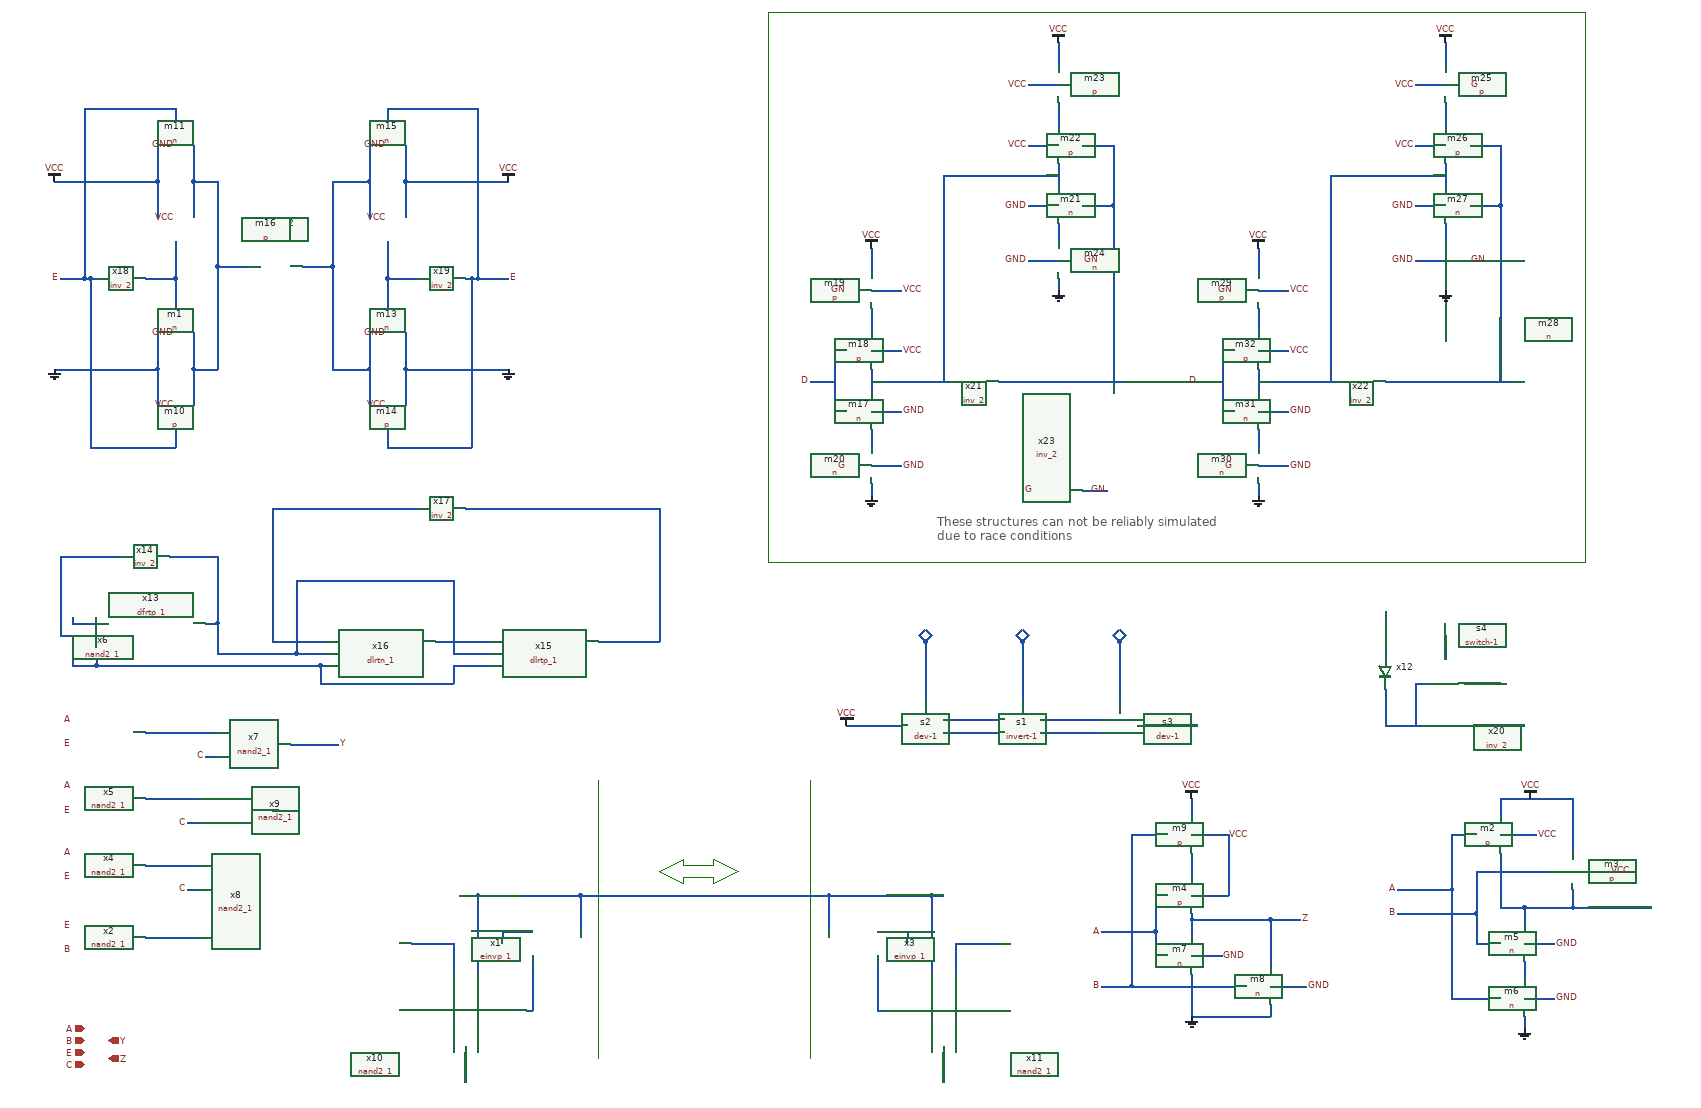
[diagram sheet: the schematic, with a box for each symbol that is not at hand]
v {xschem version=2.9.9 file_version=1.2 }
G {}
K {}
V {}
S {}
E {}
L 4 920 -590 920 -130 {dash=3}
L 4 1270 -590 1270 -130 {dash=3}
P 4 11 1110 -450 1060 -450 1060 -460 1020 -440 1060 -420 1060 -430 1110 -430 1110 -420 1150 -440 1110 -460 1110 -450 {}
P 4 5 1200 -1860 1200 -950 2550 -950 2550 -1860 1200 -1860 {dash=3}
T {These structures can not be reliably simulated
due to race conditions} 1480 -1030 0 0 0.6 0.6 {}
N 170 -330 260 -330 { lab=#net1}
N 170 -450 260 -450 { lab=#net2}
N 240 -410 260 -410 { lab=C}
N 170 -560 260 -560 { lab=#net3}
N 240 -520 260 -520 { lab=C}
N 270 -630 290 -630 { lab=C}
N 410 -650 490 -650 { lab=Y}
N 170 -670 290 -670 { lab=#net4}
N 380 -540 390 -540 { lab=#net5}
N 890 -400 890 -340 { lab=#net6}
N 890 -400 1300 -400 { lab=#net6}
N 720 -400 720 -270 { lab=#net6}
N 700 -150 700 -90 { lab=#net7}
N 680 -320 680 -270 { lab=#net8}
N 610 -320 680 -320 { lab=#net8}
N 810 -300 810 -210 { lab=#net9}
N 800 -210 810 -210 { lab=#net9}
N 690 -400 720 -400 { lab=#net6}
N 1470 -400 1490 -400 { lab=#net6}
N 760 -340 810 -340 { lab=#net10}
N 1300 -400 1300 -340 { lab=#net6}
N 1470 -400 1470 -270 { lab=#net6}
N 1490 -150 1490 -90 { lab=#net11}
N 1510 -320 1510 -270 { lab=#net12}
N 1510 -320 1580 -320 { lab=#net12}
N 1380 -300 1380 -210 { lab=#net13}
N 1380 -210 1390 -210 { lab=#net13}
N 1380 -340 1430 -340 { lab=#net14}
N 760 -340 760 -320 { lab=#net10}
N 1430 -340 1430 -320 { lab=#net14}
N 720 -400 890 -400 { lab=#net6}
N 1300 -400 1470 -400 { lab=#net6}
N 380 -820 470 -820 { lab=#net15}
N 420 -800 470 -800 { lab=#net16}
N 460 -780 470 -780 { lab=#net17}
N 650 -820 740 -820 { lab=#net18}
N 460 -780 460 -750 { lab=#net17}
N 460 -750 680 -750 { lab=#net17}
N 680 -780 680 -750 { lab=#net17}
N 680 -780 740 -780 { lab=#net17}
N 920 -820 1020 -820 { lab=#net19}
N 420 -920 420 -800 { lab=#net16}
N 680 -800 740 -800 { lab=#net16}
N 420 -920 680 -920 { lab=#net16}
N 680 -920 680 -800 { lab=#net16}
N 270 -850 290 -850 { lab=#net16}
N 290 -960 290 -850 { lab=#net16}
N 210 -960 290 -960 { lab=#net16}
N 30 -960 130 -960 { lab=#net20}
N 30 -960 30 -830 { lab=#net20}
N 30 -830 90 -830 { lab=#net20}
N 50 -850 90 -850 { lab=#net21}
N 50 -860 50 -850 { lab=#net21}
N 90 -780 460 -780 { lab=#net17}
N 90 -810 90 -780 { lab=#net17}
N 50 -780 90 -780 { lab=#net17}
N 50 -790 50 -780 { lab=#net17}
N 1900 -360 1900 -330 { lab=Z}
N 1900 -270 1900 -200 { lab=GND}
N 2030 -220 2030 -200 { lab=GND}
N 2030 -360 2030 -280 { lab=Z}
N 1800 -250 1990 -250 { lab=B}
N 1800 -500 1800 -250 { lab=B}
N 1840 -340 1840 -300 { lab=A}
N 1840 -300 1860 -300 { lab=A}
N 1750 -340 1840 -340 { lab=A}
N 1750 -250 1800 -250 { lab=B}
N 1900 -300 1950 -300 { lab=GND}
N 2030 -250 2090 -250 { lab=GND}
N 1900 -470 1900 -430 { lab=#net22}
N 1900 -560 1900 -530 { lab=VCC}
N 2030 -360 2080 -360 { lab=Z}
N 1800 -500 1860 -500 { lab=B}
N 1840 -400 1860 -400 { lab=A}
N 1900 -500 1960 -500 { lab=VCC}
N 1900 -400 1960 -400 { lab=VCC}
N 1960 -500 1960 -400 { lab=VCC}
N 1900 -200 2030 -200 { lab=GND}
N 2450 -290 2450 -260 { lab=#net23}
N 2450 -320 2500 -320 { lab=GND}
N 2450 -230 2500 -230 { lab=GND}
N 2410 -500 2470 -500 { lab=VCC}
N 2530 -440 2590 -440 { lab=VCC}
N 2530 -410 2530 -380 { lab=#net24}
N 2450 -380 2530 -380 { lab=#net24}
N 2410 -470 2410 -380 { lab=#net24}
N 2450 -380 2450 -350 { lab=#net24}
N 2410 -560 2410 -530 { lab=VCC}
N 2410 -560 2530 -560 { lab=VCC}
N 2530 -560 2530 -470 { lab=VCC}
N 2450 -200 2450 -180 { lab=GND}
N 2370 -440 2490 -440 { lab=B}
N 2370 -370 2370 -320 { lab=B}
N 2370 -320 2410 -320 { lab=B}
N 2330 -230 2410 -230 { lab=A}
N 2330 -410 2330 -230 { lab=A}
N 2330 -500 2370 -500 { lab=A}
N 2240 -370 2370 -370 { lab=B}
N 2240 -410 2330 -410 { lab=A}
N 2530 -380 2660 -380 { lab=#net24}
N 700 -1040 1020 -1040 { lab=#net19}
N 1020 -1040 1020 -820 { lab=#net19}
N 380 -1040 620 -1040 { lab=#net15}
N 380 -1040 380 -820 { lab=#net15}
N 380 -800 420 -800 { lab=#net16}
N 1900 -360 2030 -360 { lab=Z}
N 1840 -400 1840 -340 { lab=A}
N 2410 -380 2450 -380 { lab=#net24}
N 2370 -440 2370 -370 { lab=B}
N 2330 -500 2330 -410 { lab=A}
N 1900 -370 1900 -360 { lab=Z}
N 190 -1270 190 -1210 { lab=GND}
N 250 -1270 250 -1210 { lab=#net25}
N 20 -1270 190 -1270 { lab=GND}
N 250 -1270 290 -1270 { lab=#net25}
N 220 -1170 220 -1140 { lab=E}
N 80 -1420 90 -1420 { lab=E}
N 190 -1580 190 -1520 { lab=VCC}
N 250 -1580 250 -1520 { lab=#net25}
N 20 -1580 190 -1580 { lab=VCC}
N 250 -1580 290 -1580 { lab=#net25}
N 220 -1420 220 -1370 { lab=#net26}
N 170 -1420 220 -1420 { lab=#net26}
N 290 -1440 290 -1270 { lab=#net25}
N 290 -1440 340 -1440 { lab=#net25}
N 220 -1700 220 -1680 { lab=E}
N 70 -1700 70 -1420 { lab=E}
N 70 -1700 220 -1700 { lab=E}
N 80 -1420 80 -1140 { lab=E}
N 80 -1140 220 -1140 { lab=E}
N 540 -1270 540 -1210 { lab=#net27}
N 600 -1270 600 -1210 { lab=GND}
N 600 -1270 770 -1270 { lab=GND}
N 480 -1270 540 -1270 { lab=#net27}
N 570 -1170 570 -1140 { lab=E}
N 720 -1420 770 -1420 { lab=E}
N 540 -1580 540 -1520 { lab=#net27}
N 600 -1580 600 -1520 { lab=VCC}
N 600 -1580 770 -1580 { lab=VCC}
N 480 -1580 540 -1580 { lab=#net27}
N 570 -1420 570 -1370 { lab=#net28}
N 570 -1420 620 -1420 { lab=#net28}
N 480 -1440 480 -1270 { lab=#net27}
N 430 -1440 480 -1440 { lab=#net27}
N 570 -1700 720 -1700 { lab=E}
N 570 -1700 570 -1680 { lab=E}
N 720 -1700 720 -1420 { lab=E}
N 710 -1420 710 -1140 { lab=E}
N 570 -1140 710 -1140 { lab=E}
N 190 -1330 190 -1270 { lab=GND}
N 250 -1330 250 -1270 { lab=#net25}
N 190 -1640 190 -1580 { lab=VCC}
N 250 -1640 250 -1580 { lab=#net25}
N 220 -1480 220 -1420 { lab=#net26}
N 290 -1580 290 -1440 { lab=#net25}
N 30 -1420 70 -1420 { lab=E}
N 70 -1420 80 -1420 { lab=E}
N 600 -1330 600 -1270 { lab=GND}
N 540 -1330 540 -1270 { lab=#net27}
N 600 -1640 600 -1580 { lab=VCC}
N 540 -1640 540 -1580 { lab=#net27}
N 570 -1480 570 -1420 { lab=#net28}
N 480 -1580 480 -1440 { lab=#net27}
N 710 -1420 720 -1420 { lab=E}
N 700 -1420 710 -1420 { lab=E}
N 290 -800 380 -800 { lab=#net16}
N 290 -850 290 -800 { lab=#net16}
N 2220 -870 2220 -800 { lab=#net29}
N 2220 -740 2220 -680 { lab=#net30}
N 2220 -680 2280 -680 { lab=#net30}
N 2360 -680 2450 -680 { lab=#net31}
N 1370 -1170 1370 -1140 { lab=#net32}
N 1370 -1270 1370 -1230 { lab=#net33}
N 1370 -1370 1370 -1330 { lab=#net34}
N 1370 -1470 1370 -1430 { lab=VCC}
N 1370 -1080 1370 -1060 { lab=GND}
N 1370 -1110 1420 -1110 { lab=GND}
N 1370 -1200 1420 -1200 { lab=GND}
N 1370 -1300 1420 -1300 { lab=VCC}
N 1370 -1400 1420 -1400 { lab=VCC}
N 1310 -1300 1330 -1300 { lab=D}
N 1310 -1200 1330 -1200 { lab=D}
N 1370 -1250 1500 -1250 { lab=#net33}
N 1310 -1300 1310 -1200 { lab=D}
N 1270 -1250 1310 -1250 { lab=D}
N 2350 -750 2410 -750 { lab=#net35}
N 2270 -750 2290 -750 { lab=#net30}
N 2270 -750 2270 -680 { lab=#net30}
N 2320 -830 2320 -790 { lab=#net36}
N 1680 -1510 1680 -1480 { lab=#net37}
N 1680 -1610 1680 -1570 { lab=#net33}
N 1680 -1710 1680 -1670 { lab=#net38}
N 1680 -1810 1680 -1770 { lab=VCC}
N 1680 -1420 1680 -1400 { lab=GND}
N 1630 -1450 1680 -1450 { lab=GND}
N 1630 -1540 1680 -1540 { lab=GND}
N 1630 -1640 1680 -1640 { lab=VCC}
N 1630 -1740 1680 -1740 { lab=VCC}
N 1720 -1640 1770 -1640 { lab=#net39}
N 1720 -1540 1770 -1540 { lab=#net39}
N 1770 -1640 1770 -1540 { lab=#net39}
N 1770 -1540 1770 -1250 { lab=#net39}
N 1490 -1590 1680 -1590 { lab=#net33}
N 1700 -1250 1790 -1250 { lab=#net39}
N 1580 -1250 1630 -1250 { lab=#net39}
N 1630 -1250 1700 -1250 { lab=#net39}
N 1490 -1590 1490 -1250 { lab=#net33}
N 1720 -1070 1760 -1070 { lab=GN}
N 1490 -670 1590 -670 { lab=#net40}
N 1490 -690 1590 -690 { lab=#net41}
N 1650 -670 1750 -670 { lab=#net42}
N 1650 -690 1750 -690 { lab=#net43}
N 1810 -680 1910 -680 { lab=#net44}
N 1330 -680 1430 -680 { lab=VCC}
N 1460 -820 1460 -720 { lab=#net45}
N 1620 -820 1620 -720 { lab=#net46}
N 1780 -820 1780 -720 { lab=#net47}
N 1450 -830 1460 -820 { lab=#net45}
N 1450 -830 1460 -840 { lab=#net45}
N 1460 -840 1470 -830 { lab=#net45}
N 1460 -820 1470 -830 { lab=#net45}
N 1610 -830 1620 -820 { lab=#net46}
N 1610 -830 1620 -840 { lab=#net46}
N 1620 -840 1630 -830 { lab=#net46}
N 1620 -820 1630 -830 { lab=#net46}
N 1770 -830 1780 -820 { lab=#net47}
N 1770 -830 1780 -840 { lab=#net47}
N 1780 -840 1790 -830 { lab=#net47}
N 1780 -820 1790 -830 { lab=#net47}
N 2010 -1170 2010 -1140 { lab=#net48}
N 2010 -1270 2010 -1230 { lab=#net49}
N 2010 -1370 2010 -1330 { lab=#net50}
N 2010 -1470 2010 -1430 { lab=VCC}
N 2010 -1080 2010 -1060 { lab=GND}
N 2010 -1110 2060 -1110 { lab=GND}
N 2010 -1200 2060 -1200 { lab=GND}
N 2010 -1300 2060 -1300 { lab=VCC}
N 2010 -1400 2060 -1400 { lab=VCC}
N 1950 -1300 1970 -1300 { lab=D}
N 1950 -1200 1970 -1200 { lab=D}
N 2010 -1250 2140 -1250 { lab=#net49}
N 1950 -1300 1950 -1200 { lab=D}
N 1910 -1250 1950 -1250 { lab=D}
N 2320 -1510 2320 -1480 { lab=#net51}
N 2320 -1610 2320 -1570 { lab=#net49}
N 2320 -1710 2320 -1670 { lab=#net52}
N 2320 -1810 2320 -1770 { lab=VCC}
N 2320 -1420 2320 -1400 { lab=GND}
N 2270 -1450 2320 -1450 { lab=GND}
N 2270 -1540 2320 -1540 { lab=GND}
N 2270 -1640 2320 -1640 { lab=VCC}
N 2270 -1740 2320 -1740 { lab=VCC}
N 2360 -1640 2410 -1640 { lab=#net53}
N 2360 -1540 2410 -1540 { lab=#net53}
N 2410 -1640 2410 -1540 { lab=#net53}
N 2410 -1540 2410 -1250 { lab=#net53}
N 2130 -1590 2320 -1590 { lab=#net49}
N 2340 -1250 2430 -1250 { lab=#net53}
N 2220 -1250 2270 -1250 { lab=#net53}
N 2270 -1250 2340 -1250 { lab=#net53}
N 2130 -1590 2130 -1250 { lab=#net49}
C {opin.sym} 110 -160 0 0 { name=p16 lab=Y }
C {inv_2.sym} 1680 -1070 0 0 {name=x23 VGND=VGND VNB=VNB VPB=VPB VPWR=VPWR prefix=sky130_fd_sc_hd__ }
C {ipin.sym} 70 -180 0 0 { name=p20 lab=A }
C {opin.sym} 110 -130 0 0 { name=p4 lab=Z }
C {ipin.sym} 70 -120 0 0 { name=p5 lab=C }
C {title.sym} 160 -30 0 0 {name=l1 author="Stefan Schippers"}
C {lab_pin.sym} 50 -350 0 0 {name=p1 lab=E}
C {nand2_1.sym} 110 -330 0 0 {name=x2 VGND=VGND VNB=VNB VPB=VPB VPWR=VPWR prefix=sky130_fd_sc_hd__ }
C {lab_pin.sym} 50 -310 0 0 {name=p2 lab=B}
C {lab_pin.sym} 50 -470 0 0 {name=p10 lab=A}
C {nand2_1.sym} 110 -450 0 0 {name=x4 VGND=VGND VNB=VNB VPB=VPB VPWR=VPWR prefix=sky130_fd_sc_hd__ }
C {nand2_1.sym} 320 -430 0 0 {name=x8 VGND=VGND VNB=VNB VPB=VPB VPWR=VPWR prefix=sky130_fd_sc_hd__ }
C {lab_pin.sym} 50 -580 0 0 {name=p12 lab=A}
C {nand2_1.sym} 110 -560 0 0 {name=x5 VGND=VGND VNB=VNB VPB=VPB VPWR=VPWR prefix=sky130_fd_sc_hd__ }
C {lab_pin.sym} 50 -540 0 0 {name=p13 lab=E}
C {nand2_1.sym} 320 -540 0 0 {name=x9 VGND=VGND VNB=VNB VPB=VPB VPWR=VPWR prefix=sky130_fd_sc_hd__ }
C {lab_pin.sym} 50 -690 0 0 {name=p14 lab=A}
C {nand2_1.sym} 110 -670 0 0 {name=x6 VGND=VGND VNB=VNB VPB=VPB VPWR=VPWR prefix=sky130_fd_sc_hd__ }
C {lab_pin.sym} 50 -650 0 0 {name=p15 lab=E}
C {nand2_1.sym} 350 -650 0 0 {name=x7 VGND=VGND VNB=VNB VPB=VPB VPWR=VPWR prefix=sky130_fd_sc_hd__ }
C {lab_pin.sym} 490 -650 0 1 {name=p3 lab=Y}
C {lab_pin.sym} 270 -630 0 0 {name=p7 lab=C}
C {lab_pin.sym} 240 -520 0 0 {name=p8 lab=C}
C {lab_pin.sym} 240 -410 0 0 {name=p9 lab=C}
C {noconn.sym} 380 -430 0 1 {name=l2}
C {einvp_1.sym} 850 -340 0 0 {name=x1 VGND=VGND VNB=VNB VPB=VPB VPWR=VPWR prefix=sky130_fd_sc_hd__ }
C {nand2_1.sym} 700 -210 1 0 {name=x10 VGND=VGND VNB=VNB VPB=VPB VPWR=VPWR prefix=sky130_fd_sc_hd__ }
C {einvp_1.sym} 1340 -340 0 1 {name=x3 VGND=VGND VNB=VNB VPB=VPB VPWR=VPWR prefix=sky130_fd_sc_hd__ }
C {nand2_1.sym} 1490 -210 3 1 {name=x11 VGND=VGND VNB=VNB VPB=VPB VPWR=VPWR prefix=sky130_fd_sc_hd__ }
C {dlrtp_1.sym} 830 -800 0 0 {name=x15 VGND=VGND VNB=VNB VPB=VPB VPWR=VPWR prefix=sky130_fd_sc_hd__ }
C {ipin.sym} 70 -140 0 0 { name=p17 lab=E }
C {dlrtn_1.sym} 560 -800 0 0 {name=x16 VGND=VGND VNB=VNB VPB=VPB VPWR=VPWR prefix=sky130_fd_sc_hd__ }
C {dfrtp_1.sym} 180 -830 0 0 {name=x13 VGND=VGND VNB=VNB VPB=VPB VPWR=VPWR prefix=sky130_fd_sc_hd__ }
C {inv_2.sym} 170 -960 0 1 {name=x14 VGND=VGND VNB=VNB VPB=VPB VPWR=VPWR prefix=sky130_fd_sc_hd__ }
C {n.sym} 1880 -300 0 0 {name=m7 model=cmosn w=wn l=lln m=1}
C {n.sym} 2010 -250 0 0 {name=m8 model=cmosn w=wn l=lln m=1}
C {lab_pin.sym} 1750 -340 0 0 {name=p24 lab=A}
C {lab_pin.sym} 1750 -250 0 0 {name=p25 lab=B}
C {lab_pin.sym} 2090 -250 0 1 {name=p27 lab=GND}
C {lab_pin.sym} 1950 -300 0 1 {name=p30 lab=GND}
C {p.sym} 1880 -400 0 0 {name=m4 model=cmosp w=wp l=lp  m=1 }
C {p.sym} 1880 -500 0 0 {name=m9 model=cmosp w=wp l=lp  m=1 }
C {lab_pin.sym} 2080 -360 0 1 {name=p26 lab=Z}
C {lab_pin.sym} 1960 -500 0 1 {name=p31 lab=VCC}
C {gnd.sym} 1900 -200 0 0 {name=l3 lab=GND}
C {vdd.sym} 1900 -560 0 0 {name=l4 lab=VCC}
C {p.sym} 2390 -500 0 0 {name=m2 model=cmosp w=wp l=lp  m=1 }
C {p.sym} 2510 -440 0 0 {name=m3 model=cmosp w=wp l=lp  m=1 }
C {n.sym} 2430 -320 0 0 {name=m5 model=cmosn w=wn l=lln m=1}
C {n.sym} 2430 -230 0 0 {name=m6 model=cmosn w=wn l=lln m=1}
C {lab_pin.sym} 2500 -320 0 1 {name=p22 lab=GND}
C {lab_pin.sym} 2500 -230 0 1 {name=p28 lab=GND}
C {lab_pin.sym} 2470 -500 0 1 {name=p29 lab=VCC}
C {lab_pin.sym} 2590 -440 0 1 {name=p32 lab=VCC}
C {vdd.sym} 2460 -560 0 0 {name=l11 lab=VCC}
C {gnd.sym} 2450 -180 0 0 {name=l12 lab=GND}
C {lab_pin.sym} 2240 -370 0 0 {name=p21 lab=B}
C {lab_pin.sym} 2240 -410 0 0 {name=p23 lab=A}
C {inv_2.sym} 660 -1040 0 1 {name=x17 VGND=VGND VNB=VNB VPB=VPB VPWR=VPWR prefix=sky130_fd_sc_hd__ }
C {n.sym} 220 -1350 1 0 {name=m1 model=cmosn w=wn l=lln m=1}
C {lab_pin.sym} 220 -1330 1 1 {name=p6 lab=GND}
C {p.sym} 220 -1190 3 0 {name=m10 model=cmosp w=wp l=lp  m=1 }
C {lab_pin.sym} 220 -1210 3 1 {name=p18 lab=VCC}
C {inv_2.sym} 130 -1420 0 0 {name=x18 VGND=VGND VNB=VNB VPB=VPB VPWR=VPWR prefix=sky130_fd_sc_hd__ }
C {n.sym} 220 -1660 1 0 {name=m11 model=cmosn w=wn l=lln m=1}
C {lab_pin.sym} 220 -1640 1 1 {name=p33 lab=GND}
C {p.sym} 220 -1500 3 0 {name=m12 model=cmosp w=wp l=lp  m=1 }
C {lab_pin.sym} 220 -1520 3 1 {name=p34 lab=VCC}
C {vdd.sym} 20 -1580 0 0 {name=l5 lab=VCC}
C {gnd.sym} 20 -1270 0 0 {name=l6 lab=GND}
C {n.sym} 570 -1350 1 0 {name=m13 model=cmosn w=wn l=lln m=1}
C {lab_pin.sym} 570 -1330 1 1 {name=p35 lab=GND}
C {p.sym} 570 -1190 3 0 {name=m14 model=cmosp w=wp l=lp  m=1 }
C {lab_pin.sym} 570 -1210 3 1 {name=p36 lab=VCC}
C {inv_2.sym} 660 -1420 0 1 {name=x19 VGND=VGND VNB=VNB VPB=VPB VPWR=VPWR prefix=sky130_fd_sc_hd__ }
C {n.sym} 570 -1660 1 0 {name=m15 model=cmosn w=wn l=lln m=1}
C {lab_pin.sym} 570 -1640 1 1 {name=p37 lab=GND}
C {p.sym} 570 -1500 3 0 {name=m16 model=cmosp w=wp l=lp  m=1 }
C {lab_pin.sym} 570 -1520 3 1 {name=p38 lab=VCC}
C {vdd.sym} 770 -1580 0 1 {name=l7 lab=VCC}
C {gnd.sym} 770 -1270 0 1 {name=l8 lab=GND}
C {lab_pin.sym} 30 -1420 0 0 {name=p39 lab=E}
C {lab_pin.sym} 770 -1420 0 1 {name=p40 lab=E}
C {n.sym} 2340 -1450 0 1 {name=m28 model=cmosn w=wn l=lln m=1}
C {n.sym} 2340 -1540 0 1 {name=m27 model=cmosn w=wn l=lln m=1}
C {n.sym} 1700 -1540 0 1 {name=m21 model=cmosn w=wn l=lln m=1}
C {n.sym} 1700 -1450 0 1 {name=m24 model=cmosn w=wn l=lln m=1}
C {p.sym} 1350 -1400 0 0 {name=m19 model=cmosp w=wp l=lp  m=1 }
C {n.sym} 1350 -1110 0 0 {name=m20 model=cmosn w=wn l=lln m=1}
C {vdd.sym} 1370 -1470 0 0 {name=l10 lab=VCC}
C {gnd.sym} 1370 -1060 0 0 {name=l13 lab=GND}
C {lab_pin.sym} 1420 -1110 0 1 {name=p41 lab=GND}
C {lab_pin.sym} 1420 -1200 0 1 {name=p42 lab=GND}
C {lab_pin.sym} 1420 -1300 0 1 {name=p43 lab=VCC}
C {lab_pin.sym} 1420 -1400 0 1 {name=p44 lab=VCC}
C {switch-1.sym} 2320 -750 0 0 {name=s4}
C {inv_2.sym} 1540 -1250 0 0 {name=x21 VGND=VGND VNB=VNB VPB=VPB VPWR=VPWR prefix=sky130_fd_sc_hd__ }
C {inv_2.sym} 2320 -680 0 0 {name=x20 VGND=VGND VNB=VNB VPB=VPB VPWR=VPWR prefix=sky130_fd_sc_hd__ }
C {n.sym} 1350 -1200 0 0 {name=m17 model=cmosn w=wn l=lln m=1}
C {p.sym} 1350 -1300 0 0 {name=m18 model=cmosp w=wp l=lp  m=1 }
C {diode_3.sym} 2220 -770 0 0 {name=x12 VTH=0.6 RON=10 ROFF=1G}
C {vdd.sym} 1680 -1810 0 1 {name=l14 lab=VCC}
C {gnd.sym} 1680 -1400 0 1 {name=l15 lab=GND}
C {lab_pin.sym} 1630 -1450 0 0 {name=p45 lab=GND}
C {lab_pin.sym} 1630 -1540 0 0 {name=p46 lab=GND}
C {lab_pin.sym} 1630 -1640 0 0 {name=p47 lab=VCC}
C {lab_pin.sym} 1630 -1740 0 0 {name=p48 lab=VCC}
C {lab_pin.sym} 50 -430 0 0 {name=p11 lab=E}
C {lab_wire.sym} 1760 -1070 0 0 {name=l49 lab=GN}
C {lab_pin.sym} 1270 -1250 0 0 {name=p51 lab=D}
C {lab_pin.sym} 1330 -1110 0 0 {name=p52 lab=G}
C {lab_pin.sym} 1330 -1400 0 0 {name=p53 lab=GN}
C {lab_pin.sym} 1720 -1450 0 1 {name=p54 lab=GN}
C {lab_pin.sym} 1720 -1740 0 1 {name=p55 lab=G}
C {lab_pin.sym} 1640 -1070 0 0 {name=p57 lab=G}
C {ipin.sym} 70 -160 0 0 { name=p19 lab=B }
C {invert-1.sym} 1620 -680 0 0 {name=s1}
C {dev-1.sym} 1460 -680 0 0 {name=s2}
C {dev-1.sym} 1780 -680 0 1 {name=s3}
C {vdd.sym} 1330 -680 0 0 {name=l9 lab=VCC}
C {p.sym} 2340 -1740 0 1 {name=m25 model=cmosp w=wp l=lp  m=1 }
C {p.sym} 2340 -1640 0 1 {name=m26 model=cmosp w=wp l=lp  m=1 }
C {p.sym} 1700 -1640 0 1 {name=m22 model=cmosp w=wp l=lp  m=1 }
C {p.sym} 1700 -1740 0 1 {name=m23 model=cmosp w=wp l=lp  m=1 }
C {p.sym} 1990 -1400 0 0 {name=m29 model=cmosp w=wp l=lp  m=1 }
C {n.sym} 1990 -1110 0 0 {name=m30 model=cmosn w=wn l=lln m=1}
C {vdd.sym} 2010 -1470 0 0 {name=l16 lab=VCC}
C {gnd.sym} 2010 -1060 0 0 {name=l17 lab=GND}
C {lab_pin.sym} 2060 -1110 0 1 {name=p49 lab=GND}
C {lab_pin.sym} 2060 -1200 0 1 {name=p50 lab=GND}
C {lab_pin.sym} 2060 -1300 0 1 {name=p58 lab=VCC}
C {lab_pin.sym} 2060 -1400 0 1 {name=p59 lab=VCC}
C {inv_2.sym} 2180 -1250 0 0 {name=x22 VGND=VGND VNB=VNB VPB=VPB VPWR=VPWR prefix=sky130_fd_sc_hd__ }
C {n.sym} 1990 -1200 0 0 {name=m31 model=cmosn w=wn l=lln m=1}
C {p.sym} 1990 -1300 0 0 {name=m32 model=cmosp w=wp l=lp  m=1 }
C {vdd.sym} 2320 -1810 0 1 {name=l18 lab=VCC}
C {gnd.sym} 2320 -1400 0 1 {name=l19 lab=GND}
C {lab_pin.sym} 2270 -1450 0 0 {name=p60 lab=GND}
C {lab_pin.sym} 2270 -1540 0 0 {name=p61 lab=GND}
C {lab_pin.sym} 2270 -1640 0 0 {name=p62 lab=VCC}
C {lab_pin.sym} 2270 -1740 0 0 {name=p63 lab=VCC}
C {lab_pin.sym} 1910 -1250 0 0 {name=p64 lab=D}
C {lab_pin.sym} 1970 -1110 0 0 {name=p65 lab=G}
C {lab_pin.sym} 1970 -1400 0 0 {name=p66 lab=GN}
C {lab_pin.sym} 2360 -1450 0 1 {name=p67 lab=GN}
C {lab_pin.sym} 2360 -1740 0 1 {name=p68 lab=G}
